VERSION 5.8 ;
BUSBITCHARS "[]" ;
DIVIDERCHAR "/" ;
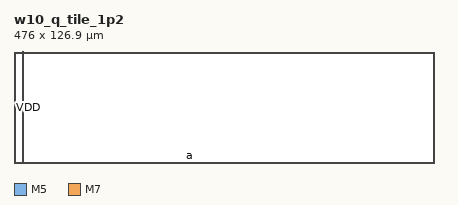
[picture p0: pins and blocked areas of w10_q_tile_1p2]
MACRO w10_q_tile_1p2
  CLASS BLOCK ;
  FOREIGN w10_q_tile_1p2 0 0 ;
  SIZE 476.0 BY 126.9 ;
  PIN a
    DIRECTION INPUT ;
    USE SIGNAL ;
    PORT
      LAYER M5 ;
        RECT 200.0 0 200.024 0.084 ;
    END
  END a
  PIN VDD
    DIRECTION INOUT ;
    USE POWER ;
    PORT
      LAYER M7 ;
        RECT 10 0 10.544 126.9 ;
    END
  END VDD
END w10_q_tile_1p2
END LIBRARY
